VERSION 5.4 ;
NAMESCASESENSITIVE ON ;
BUSBITCHARS "[]" ;
DIVIDERCHAR "/" ;
UNITS
  DATABASE MICRONS 2000 ;
END UNITS
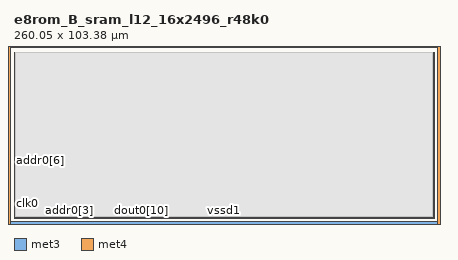
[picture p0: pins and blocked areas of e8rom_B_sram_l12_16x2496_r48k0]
MACRO e8rom_B_sram_l12_16x2496_r48k0
   CLASS BLOCK ;
   SIZE 260.05 BY 103.38 ;
   SYMMETRY X Y R90 ;
   PIN clk0
      DIRECTION INPUT ;
      PORT
         LAYER met3 ;
         RECT  -7.48 8.99 -7.1 9.37 ;
      END
   END clk0
   PIN cs0
      DIRECTION INPUT ;
      PORT
         LAYER met4 ;
         RECT  10.585 -7.48 10.965 -7.1 ;
      END
   END cs0
   PIN addr0[0]
      DIRECTION INPUT ;
      PORT
         LAYER met4 ;
         RECT  28.15 -7.48 28.53 -7.1 ;
      END
   END addr0[0]
   PIN addr0[1]
      DIRECTION INPUT ;
      PORT
         LAYER met4 ;
         RECT  30.19 -7.48 30.57 -7.1 ;
      END
   END addr0[1]
   PIN addr0[2]
      DIRECTION INPUT ;
      PORT
         LAYER met4 ;
         RECT  32.23 -7.48 32.61 -7.1 ;
      END
   END addr0[2]
   PIN addr0[3]
      DIRECTION INPUT ;
      PORT
         LAYER met4 ;
         RECT  34.27 -7.48 34.65 -7.1 ;
      END
   END addr0[3]
   PIN addr0[4]
      DIRECTION INPUT ;
      PORT
         LAYER met3 ;
         RECT  -7.48 33.89 -7.1 34.27 ;
      END
   END addr0[4]
   PIN addr0[5]
      DIRECTION INPUT ;
      PORT
         LAYER met3 ;
         RECT  -7.48 34.635 -7.1 35.015 ;
      END
   END addr0[5]
   PIN addr0[6]
      DIRECTION INPUT ;
      PORT
         LAYER met3 ;
         RECT  -7.48 35.325 -7.1 35.705 ;
      END
   END addr0[6]
   PIN addr0[7]
      DIRECTION INPUT ;
      PORT
         LAYER met3 ;
         RECT  -7.48 32.42 -7.1 32.8 ;
      END
   END addr0[7]
   PIN addr0[8]
      DIRECTION INPUT ;
      PORT
         LAYER met3 ;
         RECT  -7.48 36.015 -7.1 36.395 ;
      END
   END addr0[8]
   PIN addr0[9]
      DIRECTION INPUT ;
      PORT
         LAYER met3 ;
         RECT  -7.48 31.73 -7.1 32.11 ;
      END
   END addr0[9]
   PIN dout0[0]
      DIRECTION OUTPUT ;
      PORT
         LAYER met4 ;
         RECT  63.155 -7.48 63.535 -7.1 ;
      END
   END dout0[0]
   PIN dout0[1]
      DIRECTION OUTPUT ;
      PORT
         LAYER met4 ;
         RECT  64.695 -7.48 65.075 -7.1 ;
      END
   END dout0[1]
   PIN dout0[2]
      DIRECTION OUTPUT ;
      PORT
         LAYER met4 ;
         RECT  66.235 -7.48 66.615 -7.1 ;
      END
   END dout0[2]
   PIN dout0[3]
      DIRECTION OUTPUT ;
      PORT
         LAYER met4 ;
         RECT  67.775 -7.48 68.155 -7.1 ;
      END
   END dout0[3]
   PIN dout0[4]
      DIRECTION OUTPUT ;
      PORT
         LAYER met4 ;
         RECT  69.315 -7.48 69.695 -7.1 ;
      END
   END dout0[4]
   PIN dout0[5]
      DIRECTION OUTPUT ;
      PORT
         LAYER met4 ;
         RECT  70.855 -7.48 71.235 -7.1 ;
      END
   END dout0[5]
   PIN dout0[6]
      DIRECTION OUTPUT ;
      PORT
         LAYER met4 ;
         RECT  72.395 -7.48 72.775 -7.1 ;
      END
   END dout0[6]
   PIN dout0[7]
      DIRECTION OUTPUT ;
      PORT
         LAYER met4 ;
         RECT  73.935 -7.48 74.315 -7.1 ;
      END
   END dout0[7]
   PIN dout0[8]
      DIRECTION OUTPUT ;
      PORT
         LAYER met4 ;
         RECT  75.475 -7.48 75.855 -7.1 ;
      END
   END dout0[8]
   PIN dout0[9]
      DIRECTION OUTPUT ;
      PORT
         LAYER met4 ;
         RECT  77.015 -7.48 77.395 -7.1 ;
      END
   END dout0[9]
   PIN dout0[10]
      DIRECTION OUTPUT ;
      PORT
         LAYER met4 ;
         RECT  78.555 -7.48 78.935 -7.1 ;
      END
   END dout0[10]
   PIN dout0[11]
      DIRECTION OUTPUT ;
      PORT
         LAYER met4 ;
         RECT  80.095 -7.48 80.475 -7.1 ;
      END
   END dout0[11]
   PIN dout0[12]
      DIRECTION OUTPUT ;
      PORT
         LAYER met4 ;
         RECT  81.635 -7.48 82.015 -7.1 ;
      END
   END dout0[12]
   PIN dout0[13]
      DIRECTION OUTPUT ;
      PORT
         LAYER met4 ;
         RECT  83.175 -7.48 83.555 -7.1 ;
      END
   END dout0[13]
   PIN dout0[14]
      DIRECTION OUTPUT ;
      PORT
         LAYER met4 ;
         RECT  84.715 -7.48 85.095 -7.1 ;
      END
   END dout0[14]
   PIN dout0[15]
      DIRECTION OUTPUT ;
      PORT
         LAYER met4 ;
         RECT  86.255 -7.48 86.635 -7.1 ;
      END
   END dout0[15]
   PIN vccd1
      DIRECTION INOUT ;
      USE POWER ; 
      SHAPE ABUTMENT ; 
      PORT
         LAYER met4 ;
         RECT  -7.48 -7.48 -5.74 110.86 ;
         LAYER met4 ;
         RECT  265.79 -7.48 267.53 110.86 ;
         LAYER met3 ;
         RECT  -7.48 -7.48 267.53 -5.74 ;
         LAYER met3 ;
         RECT  -7.48 109.12 267.53 110.86 ;
      END
   END vccd1
   PIN vssd1
      DIRECTION INOUT ;
      USE GROUND ; 
      SHAPE ABUTMENT ; 
      PORT
         LAYER met3 ;
         RECT  -4.0 105.64 264.05 107.38 ;
         LAYER met4 ;
         RECT  -4.0 -4.0 -2.26 107.38 ;
         LAYER met4 ;
         RECT  262.31 -4.0 264.05 107.38 ;
         LAYER met3 ;
         RECT  -4.0 -4.0 264.05 -2.26 ;
      END
   END vssd1
   OBS
   LAYER  met1 ;
      RECT  0.62 0.62 259.43 102.76 ;
   LAYER  met2 ;
      RECT  0.62 0.62 259.43 102.76 ;
   LAYER  met3 ;
      RECT  0.62 0.62 259.43 102.76 ;
   LAYER  met4 ;
      RECT  0.62 0.62 259.43 102.76 ;
   END
END    e8rom_B_sram_l12_16x2496_r48k0
END    LIBRARY
